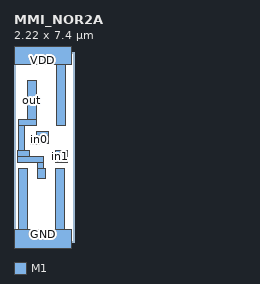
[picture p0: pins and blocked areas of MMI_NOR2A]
MACRO MMI_NOR2A
	CLASS CORE ;
	FOREIGN MMI_NOR2A 0 0 ;
	SIZE 2.22 BY 7.4 ;
	SYMMETRY X Y ;
	SITE CORE1 ;
	PIN out
		DIRECTION output ;
		USE SIGNAL ;
		PORT
			LAYER M1 ;
			RECT 0.52 4.765 0.86 6.295 ;
			LAYER M1 ;
			RECT 0.18 4.535 0.86 4.765 ;
			LAYER M1 ;
			RECT 0.18 3.555 0.41 4.535 ;
			LAYER M1 ;
			RECT 0.145 3.335 0.595 3.555 ;
			LAYER M1 ;
			RECT 0.145 3.105 1.13 3.335 ;
			LAYER M1 ;
			RECT 0.9 2.86 1.13 3.105 ;
			LAYER M1 ;
			RECT 0.9 2.48 1.24 2.86 ;
		END
		AntennaDiffArea 1.1316 ;
	END out
	PIN in1
		DIRECTION input ;
		USE SIGNAL ;
		PORT
			LAYER M1 ;
			RECT 1.625 3.5 2.075 3.555 ;
			LAYER M1 ;
			RECT 1.51 3.16 2.075 3.5 ;
			LAYER M1 ;
			RECT 1.625 3.105 2.075 3.16 ;
		END
		AntennaGateArea 0.414 ;
	END in1
	PIN GND
		DIRECTION inout ;
		USE GROUND ;
		PORT
			LAYER M1 ;
			RECT 0.18 0.5 0.52 2.86 ;
			LAYER M1 ;
			RECT 1.62 0.5 1.96 2.86 ;
			LAYER M1 ;
			RECT 0 -0.5 2.22 0.5 ;
		END
	END GND
	PIN VDD
		DIRECTION inout ;
		USE POWER ;
		PORT
			LAYER M1 ;
			RECT 0 6.9 2.22 7.9 ;
			LAYER M1 ;
			RECT 1.67 4.535 2.01 6.9 ;
		END
	END VDD
	PIN in0
		DIRECTION input ;
		USE SIGNAL ;
		PORT
			LAYER M1 ;
			RECT 0.885 4.14 1.335 4.295 ;
			LAYER M1 ;
			RECT 0.64 3.845 1.335 4.14 ;
			LAYER M1 ;
			RECT 0.64 3.8 0.98 3.845 ;
		END
		AntennaGateArea 0.414 ;
	END in0
	OBS
	END
END MMI_NOR2A
